VERSION 5.7 ;
  NOWIREEXTENSIONATPIN ON ;
  DIVIDERCHAR "/" ;
  BUSBITCHARS "[]" ;
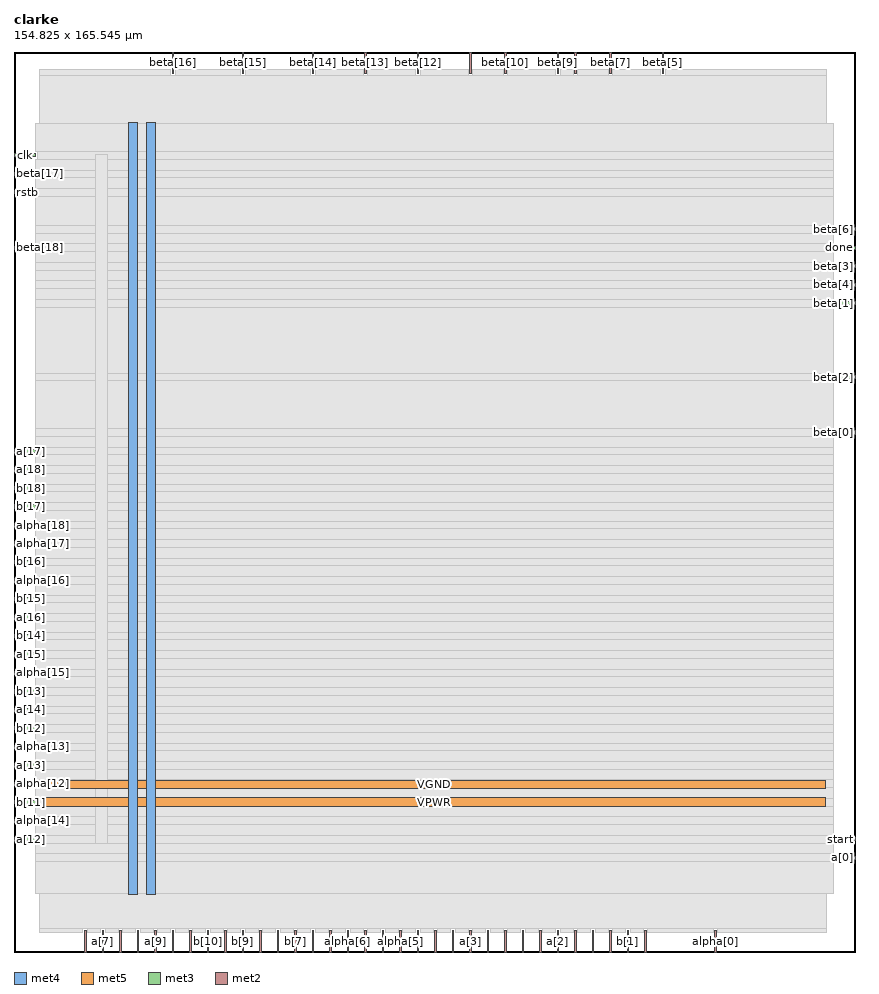
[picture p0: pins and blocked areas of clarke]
MACRO clarke
  CLASS BLOCK ;
  FOREIGN clarke ;
  ORIGIN 0.000 0.000 ;
  SIZE 154.825 BY 165.545 ;
  PIN VGND
    DIRECTION INOUT ;
    USE GROUND ;
    PORT
      LAYER met4 ;
        RECT 24.340 10.640 25.940 152.560 ;
    END
    PORT
      LAYER met5 ;
        RECT 5.280 30.030 149.280 31.630 ;
    END
  END VGND
  PIN VPWR
    DIRECTION INOUT ;
    USE POWER ;
    PORT
      LAYER met4 ;
        RECT 21.040 10.640 22.640 152.560 ;
    END
    PORT
      LAYER met5 ;
        RECT 5.280 26.730 149.280 28.330 ;
    END
  END VPWR
  PIN a[0]
    DIRECTION INPUT ;
    USE SIGNAL ;
    ANTENNAGATEAREA 0.213000 ;
    PORT
      LAYER met3 ;
        RECT 150.825 17.040 154.825 17.640 ;
    END
  END a[0]
  PIN a[10]
    DIRECTION INPUT ;
    USE SIGNAL ;
    ANTENNAGATEAREA 0.196500 ;
    PORT
      LAYER met2 ;
        RECT 12.970 0.000 13.250 4.000 ;
    END
  END a[10]
  PIN a[11]
    DIRECTION INPUT ;
    USE SIGNAL ;
    ANTENNAGATEAREA 0.213000 ;
    PORT
      LAYER met2 ;
        RECT 29.070 0.000 29.350 4.000 ;
    END
  END a[11]
  PIN a[12]
    DIRECTION INPUT ;
    USE SIGNAL ;
    ANTENNAGATEAREA 0.196500 ;
    PORT
      LAYER met3 ;
        RECT 0.000 20.440 4.000 21.040 ;
    END
  END a[12]
  PIN a[13]
    DIRECTION INPUT ;
    USE SIGNAL ;
    ANTENNAGATEAREA 0.196500 ;
    PORT
      LAYER met3 ;
        RECT 0.000 34.040 4.000 34.640 ;
    END
  END a[13]
  PIN a[14]
    DIRECTION INPUT ;
    USE SIGNAL ;
    ANTENNAGATEAREA 0.213000 ;
    PORT
      LAYER met3 ;
        RECT 0.000 44.240 4.000 44.840 ;
    END
  END a[14]
  PIN a[15]
    DIRECTION INPUT ;
    USE SIGNAL ;
    ANTENNAGATEAREA 0.196500 ;
    PORT
      LAYER met3 ;
        RECT 0.000 54.440 4.000 55.040 ;
    END
  END a[15]
  PIN a[16]
    DIRECTION INPUT ;
    USE SIGNAL ;
    ANTENNAGATEAREA 0.196500 ;
    PORT
      LAYER met3 ;
        RECT 0.000 61.240 4.000 61.840 ;
    END
  END a[16]
  PIN a[17]
    DIRECTION INPUT ;
    USE SIGNAL ;
    ANTENNAGATEAREA 0.196500 ;
    PORT
      LAYER met3 ;
        RECT 0.000 91.840 4.000 92.440 ;
    END
  END a[17]
  PIN a[18]
    DIRECTION INPUT ;
    USE SIGNAL ;
    ANTENNAGATEAREA 0.213000 ;
    PORT
      LAYER met3 ;
        RECT 0.000 88.440 4.000 89.040 ;
    END
  END a[18]
  PIN a[1]
    DIRECTION INPUT ;
    USE SIGNAL ;
    ANTENNAGATEAREA 0.196500 ;
    PORT
      LAYER met2 ;
        RECT 116.010 0.000 116.290 4.000 ;
    END
  END a[1]
  PIN a[2]
    DIRECTION INPUT ;
    USE SIGNAL ;
    ANTENNAGATEAREA 0.213000 ;
    PORT
      LAYER met2 ;
        RECT 99.910 0.000 100.190 4.000 ;
    END
  END a[2]
  PIN a[3]
    DIRECTION INPUT ;
    USE SIGNAL ;
    ANTENNAGATEAREA 0.196500 ;
    PORT
      LAYER met2 ;
        RECT 83.810 0.000 84.090 4.000 ;
    END
  END a[3]
  PIN a[4]
    DIRECTION INPUT ;
    USE SIGNAL ;
    ANTENNAGATEAREA 0.196500 ;
    PORT
      LAYER met2 ;
        RECT 109.570 0.000 109.850 4.000 ;
    END
  END a[4]
  PIN a[5]
    DIRECTION INPUT ;
    USE SIGNAL ;
    ANTENNAGATEAREA 0.196500 ;
    PORT
      LAYER met2 ;
        RECT 77.370 0.000 77.650 4.000 ;
    END
  END a[5]
  PIN a[6]
    DIRECTION INPUT ;
    USE SIGNAL ;
    ANTENNAGATEAREA 0.196500 ;
    PORT
      LAYER met2 ;
        RECT 67.710 0.000 67.990 4.000 ;
    END
  END a[6]
  PIN a[7]
    DIRECTION INPUT ;
    USE SIGNAL ;
    ANTENNAGATEAREA 0.495000 ;
    PORT
      LAYER met2 ;
        RECT 16.190 0.000 16.470 4.000 ;
    END
  END a[7]
  PIN a[8]
    DIRECTION INPUT ;
    USE SIGNAL ;
    ANTENNAGATEAREA 0.196500 ;
    PORT
      LAYER met2 ;
        RECT 19.410 0.000 19.690 4.000 ;
    END
  END a[8]
  PIN a[9]
    DIRECTION INPUT ;
    USE SIGNAL ;
    ANTENNAGATEAREA 0.196500 ;
    PORT
      LAYER met2 ;
        RECT 25.850 0.000 26.130 4.000 ;
    END
  END a[9]
  PIN alpha[0]
    DIRECTION OUTPUT ;
    USE SIGNAL ;
    ANTENNADIFFAREA 0.795200 ;
    PORT
      LAYER met2 ;
        RECT 128.890 0.000 129.170 4.000 ;
    END
  END alpha[0]
  PIN alpha[10]
    DIRECTION OUTPUT ;
    USE SIGNAL ;
    ANTENNADIFFAREA 0.795200 ;
    PORT
      LAYER met2 ;
        RECT 38.730 0.000 39.010 4.000 ;
    END
  END alpha[10]
  PIN alpha[11]
    DIRECTION OUTPUT ;
    USE SIGNAL ;
    ANTENNADIFFAREA 0.795200 ;
    PORT
      LAYER met2 ;
        RECT 32.290 0.000 32.570 4.000 ;
    END
  END alpha[11]
  PIN alpha[12]
    DIRECTION OUTPUT ;
    USE SIGNAL ;
    ANTENNADIFFAREA 0.795200 ;
    PORT
      LAYER met3 ;
        RECT 0.000 30.640 4.000 31.240 ;
    END
  END alpha[12]
  PIN alpha[13]
    DIRECTION OUTPUT ;
    USE SIGNAL ;
    ANTENNADIFFAREA 0.795200 ;
    PORT
      LAYER met3 ;
        RECT 0.000 37.440 4.000 38.040 ;
    END
  END alpha[13]
  PIN alpha[14]
    DIRECTION OUTPUT ;
    USE SIGNAL ;
    ANTENNADIFFAREA 0.795200 ;
    PORT
      LAYER met3 ;
        RECT 0.000 23.840 4.000 24.440 ;
    END
  END alpha[14]
  PIN alpha[15]
    DIRECTION OUTPUT ;
    USE SIGNAL ;
    ANTENNADIFFAREA 0.795200 ;
    PORT
      LAYER met3 ;
        RECT 0.000 51.040 4.000 51.640 ;
    END
  END alpha[15]
  PIN alpha[16]
    DIRECTION OUTPUT ;
    USE SIGNAL ;
    ANTENNADIFFAREA 0.795200 ;
    PORT
      LAYER met3 ;
        RECT 0.000 68.040 4.000 68.640 ;
    END
  END alpha[16]
  PIN alpha[17]
    DIRECTION OUTPUT ;
    USE SIGNAL ;
    ANTENNADIFFAREA 0.795200 ;
    PORT
      LAYER met3 ;
        RECT 0.000 74.840 4.000 75.440 ;
    END
  END alpha[17]
  PIN alpha[18]
    DIRECTION OUTPUT ;
    USE SIGNAL ;
    ANTENNADIFFAREA 0.795200 ;
    PORT
      LAYER met3 ;
        RECT 0.000 78.240 4.000 78.840 ;
    END
  END alpha[18]
  PIN alpha[1]
    DIRECTION OUTPUT ;
    USE SIGNAL ;
    ANTENNADIFFAREA 0.795200 ;
    PORT
      LAYER met2 ;
        RECT 106.350 0.000 106.630 4.000 ;
    END
  END alpha[1]
  PIN alpha[2]
    DIRECTION OUTPUT ;
    USE SIGNAL ;
    ANTENNADIFFAREA 0.795200 ;
    PORT
      LAYER met2 ;
        RECT 93.470 0.000 93.750 4.000 ;
    END
  END alpha[2]
  PIN alpha[3]
    DIRECTION OUTPUT ;
    USE SIGNAL ;
    ANTENNADIFFAREA 0.795200 ;
    PORT
      LAYER met2 ;
        RECT 90.250 0.000 90.530 4.000 ;
    END
  END alpha[3]
  PIN alpha[4]
    DIRECTION OUTPUT ;
    USE SIGNAL ;
    ANTENNADIFFAREA 0.795200 ;
    PORT
      LAYER met2 ;
        RECT 80.590 0.000 80.870 4.000 ;
    END
  END alpha[4]
  PIN alpha[5]
    DIRECTION OUTPUT ;
    USE SIGNAL ;
    ANTENNADIFFAREA 0.795200 ;
    PORT
      LAYER met2 ;
        RECT 70.930 0.000 71.210 4.000 ;
    END
  END alpha[5]
  PIN alpha[6]
    DIRECTION OUTPUT ;
    USE SIGNAL ;
    ANTENNADIFFAREA 0.795200 ;
    PORT
      LAYER met2 ;
        RECT 61.270 0.000 61.550 4.000 ;
    END
  END alpha[6]
  PIN alpha[7]
    DIRECTION OUTPUT ;
    USE SIGNAL ;
    ANTENNADIFFAREA 0.795200 ;
    PORT
      LAYER met2 ;
        RECT 54.830 0.000 55.110 4.000 ;
    END
  END alpha[7]
  PIN alpha[8]
    DIRECTION OUTPUT ;
    USE SIGNAL ;
    ANTENNADIFFAREA 0.795200 ;
    PORT
      LAYER met2 ;
        RECT 22.630 0.000 22.910 4.000 ;
    END
  END alpha[8]
  PIN alpha[9]
    DIRECTION OUTPUT ;
    USE SIGNAL ;
    ANTENNADIFFAREA 0.795200 ;
    PORT
      LAYER met2 ;
        RECT 45.170 0.000 45.450 4.000 ;
    END
  END alpha[9]
  PIN b[0]
    DIRECTION INPUT ;
    USE SIGNAL ;
    ANTENNAGATEAREA 0.196500 ;
    PORT
      LAYER met2 ;
        RECT 103.130 0.000 103.410 4.000 ;
    END
  END b[0]
  PIN b[10]
    DIRECTION INPUT ;
    USE SIGNAL ;
    ANTENNAGATEAREA 0.213000 ;
    PORT
      LAYER met2 ;
        RECT 35.510 0.000 35.790 4.000 ;
    END
  END b[10]
  PIN b[11]
    DIRECTION INPUT ;
    USE SIGNAL ;
    ANTENNAGATEAREA 0.196500 ;
    PORT
      LAYER met3 ;
        RECT 0.000 27.240 4.000 27.840 ;
    END
  END b[11]
  PIN b[12]
    DIRECTION INPUT ;
    USE SIGNAL ;
    ANTENNAGATEAREA 0.196500 ;
    PORT
      LAYER met3 ;
        RECT 0.000 40.840 4.000 41.440 ;
    END
  END b[12]
  PIN b[13]
    DIRECTION INPUT ;
    USE SIGNAL ;
    ANTENNAGATEAREA 0.196500 ;
    PORT
      LAYER met3 ;
        RECT 0.000 47.640 4.000 48.240 ;
    END
  END b[13]
  PIN b[14]
    DIRECTION INPUT ;
    USE SIGNAL ;
    ANTENNAGATEAREA 0.196500 ;
    PORT
      LAYER met3 ;
        RECT 0.000 57.840 4.000 58.440 ;
    END
  END b[14]
  PIN b[15]
    DIRECTION INPUT ;
    USE SIGNAL ;
    ANTENNAGATEAREA 0.196500 ;
    PORT
      LAYER met3 ;
        RECT 0.000 64.640 4.000 65.240 ;
    END
  END b[15]
  PIN b[16]
    DIRECTION INPUT ;
    USE SIGNAL ;
    ANTENNAGATEAREA 0.196500 ;
    PORT
      LAYER met3 ;
        RECT 0.000 71.440 4.000 72.040 ;
    END
  END b[16]
  PIN b[17]
    DIRECTION INPUT ;
    USE SIGNAL ;
    ANTENNAGATEAREA 0.196500 ;
    PORT
      LAYER met3 ;
        RECT 0.000 81.640 4.000 82.240 ;
    END
  END b[17]
  PIN b[18]
    DIRECTION INPUT ;
    USE SIGNAL ;
    ANTENNAGATEAREA 0.196500 ;
    PORT
      LAYER met3 ;
        RECT 0.000 85.040 4.000 85.640 ;
    END
  END b[18]
  PIN b[1]
    DIRECTION INPUT ;
    USE SIGNAL ;
    ANTENNAGATEAREA 0.196500 ;
    PORT
      LAYER met2 ;
        RECT 112.790 0.000 113.070 4.000 ;
    END
  END b[1]
  PIN b[2]
    DIRECTION INPUT ;
    USE SIGNAL ;
    ANTENNAGATEAREA 0.196500 ;
    PORT
      LAYER met2 ;
        RECT 87.030 0.000 87.310 4.000 ;
    END
  END b[2]
  PIN b[3]
    DIRECTION INPUT ;
    USE SIGNAL ;
    ANTENNAGATEAREA 0.196500 ;
    PORT
      LAYER met2 ;
        RECT 96.690 0.000 96.970 4.000 ;
    END
  END b[3]
  PIN b[4]
    DIRECTION INPUT ;
    USE SIGNAL ;
    ANTENNAGATEAREA 0.196500 ;
    PORT
      LAYER met2 ;
        RECT 74.150 0.000 74.430 4.000 ;
    END
  END b[4]
  PIN b[5]
    DIRECTION INPUT ;
    USE SIGNAL ;
    ANTENNAGATEAREA 0.196500 ;
    PORT
      LAYER met2 ;
        RECT 64.490 0.000 64.770 4.000 ;
    END
  END b[5]
  PIN b[6]
    DIRECTION INPUT ;
    USE SIGNAL ;
    ANTENNAGATEAREA 0.196500 ;
    PORT
      LAYER met2 ;
        RECT 58.050 0.000 58.330 4.000 ;
    END
  END b[6]
  PIN b[7]
    DIRECTION INPUT ;
    USE SIGNAL ;
    ANTENNAGATEAREA 0.196500 ;
    PORT
      LAYER met2 ;
        RECT 51.610 0.000 51.890 4.000 ;
    END
  END b[7]
  PIN b[8]
    DIRECTION INPUT ;
    USE SIGNAL ;
    ANTENNAGATEAREA 0.196500 ;
    PORT
      LAYER met2 ;
        RECT 48.390 0.000 48.670 4.000 ;
    END
  END b[8]
  PIN b[9]
    DIRECTION INPUT ;
    USE SIGNAL ;
    ANTENNAGATEAREA 0.196500 ;
    PORT
      LAYER met2 ;
        RECT 41.950 0.000 42.230 4.000 ;
    END
  END b[9]
  PIN beta[0]
    DIRECTION OUTPUT ;
    USE SIGNAL ;
    ANTENNADIFFAREA 0.795200 ;
    PORT
      LAYER met3 ;
        RECT 150.825 95.240 154.825 95.840 ;
    END
  END beta[0]
  PIN beta[10]
    DIRECTION OUTPUT ;
    USE SIGNAL ;
    ANTENNADIFFAREA 0.795200 ;
    PORT
      LAYER met2 ;
        RECT 90.250 161.545 90.530 165.545 ;
    END
  END beta[10]
  PIN beta[11]
    DIRECTION OUTPUT ;
    USE SIGNAL ;
    ANTENNADIFFAREA 0.795200 ;
    PORT
      LAYER met2 ;
        RECT 83.810 161.545 84.090 165.545 ;
    END
  END beta[11]
  PIN beta[12]
    DIRECTION OUTPUT ;
    USE SIGNAL ;
    ANTENNADIFFAREA 0.795200 ;
    PORT
      LAYER met2 ;
        RECT 74.150 161.545 74.430 165.545 ;
    END
  END beta[12]
  PIN beta[13]
    DIRECTION OUTPUT ;
    USE SIGNAL ;
    ANTENNADIFFAREA 0.795200 ;
    PORT
      LAYER met2 ;
        RECT 64.490 161.545 64.770 165.545 ;
    END
  END beta[13]
  PIN beta[14]
    DIRECTION OUTPUT ;
    USE SIGNAL ;
    ANTENNADIFFAREA 0.795200 ;
    PORT
      LAYER met2 ;
        RECT 54.830 161.545 55.110 165.545 ;
    END
  END beta[14]
  PIN beta[15]
    DIRECTION OUTPUT ;
    USE SIGNAL ;
    ANTENNADIFFAREA 0.795200 ;
    PORT
      LAYER met2 ;
        RECT 41.950 161.545 42.230 165.545 ;
    END
  END beta[15]
  PIN beta[16]
    DIRECTION OUTPUT ;
    USE SIGNAL ;
    ANTENNADIFFAREA 0.795200 ;
    PORT
      LAYER met2 ;
        RECT 29.070 161.545 29.350 165.545 ;
    END
  END beta[16]
  PIN beta[17]
    DIRECTION OUTPUT ;
    USE SIGNAL ;
    ANTENNADIFFAREA 0.795200 ;
    PORT
      LAYER met3 ;
        RECT 0.000 142.840 4.000 143.440 ;
    END
  END beta[17]
  PIN beta[18]
    DIRECTION OUTPUT ;
    USE SIGNAL ;
    ANTENNADIFFAREA 0.795200 ;
    PORT
      LAYER met3 ;
        RECT 0.000 129.240 4.000 129.840 ;
    END
  END beta[18]
  PIN beta[1]
    DIRECTION OUTPUT ;
    USE SIGNAL ;
    ANTENNADIFFAREA 0.445500 ;
    PORT
      LAYER met3 ;
        RECT 150.825 119.040 154.825 119.640 ;
    END
  END beta[1]
  PIN beta[2]
    DIRECTION OUTPUT ;
    USE SIGNAL ;
    ANTENNADIFFAREA 0.445500 ;
    PORT
      LAYER met3 ;
        RECT 150.825 105.440 154.825 106.040 ;
    END
  END beta[2]
  PIN beta[3]
    DIRECTION OUTPUT ;
    USE SIGNAL ;
    ANTENNADIFFAREA 0.795200 ;
    PORT
      LAYER met3 ;
        RECT 150.825 125.840 154.825 126.440 ;
    END
  END beta[3]
  PIN beta[4]
    DIRECTION OUTPUT ;
    USE SIGNAL ;
    ANTENNADIFFAREA 0.795200 ;
    PORT
      LAYER met3 ;
        RECT 150.825 122.440 154.825 123.040 ;
    END
  END beta[4]
  PIN beta[5]
    DIRECTION OUTPUT ;
    USE SIGNAL ;
    ANTENNADIFFAREA 0.795200 ;
    PORT
      LAYER met2 ;
        RECT 119.230 161.545 119.510 165.545 ;
    END
  END beta[5]
  PIN beta[6]
    DIRECTION OUTPUT ;
    USE SIGNAL ;
    ANTENNADIFFAREA 0.445500 ;
    PORT
      LAYER met3 ;
        RECT 150.825 132.640 154.825 133.240 ;
    END
  END beta[6]
  PIN beta[7]
    DIRECTION OUTPUT ;
    USE SIGNAL ;
    ANTENNADIFFAREA 0.795200 ;
    PORT
      LAYER met2 ;
        RECT 109.570 161.545 109.850 165.545 ;
    END
  END beta[7]
  PIN beta[8]
    DIRECTION OUTPUT ;
    USE SIGNAL ;
    ANTENNADIFFAREA 0.795200 ;
    PORT
      LAYER met2 ;
        RECT 103.130 161.545 103.410 165.545 ;
    END
  END beta[8]
  PIN beta[9]
    DIRECTION OUTPUT ;
    USE SIGNAL ;
    ANTENNADIFFAREA 0.795200 ;
    PORT
      LAYER met2 ;
        RECT 99.910 161.545 100.190 165.545 ;
    END
  END beta[9]
  PIN clk
    DIRECTION INPUT ;
    USE SIGNAL ;
    ANTENNAGATEAREA 0.852000 ;
    PORT
      LAYER met3 ;
        RECT 0.000 146.240 4.000 146.840 ;
    END
  END clk
  PIN done
    DIRECTION OUTPUT ;
    USE SIGNAL ;
    ANTENNADIFFAREA 0.795200 ;
    PORT
      LAYER met3 ;
        RECT 150.825 129.240 154.825 129.840 ;
    END
  END done
  PIN rstb
    DIRECTION INPUT ;
    USE SIGNAL ;
    ANTENNAGATEAREA 0.213000 ;
    PORT
      LAYER met3 ;
        RECT 0.000 139.440 4.000 140.040 ;
    END
  END rstb
  PIN start
    DIRECTION INPUT ;
    USE SIGNAL ;
    ANTENNAGATEAREA 0.159000 ;
    PORT
      LAYER met3 ;
        RECT 150.825 20.440 154.825 21.040 ;
    END
  END start
  OBS
      LAYER li1 ;
        RECT 5.520 10.795 149.040 152.405 ;
      LAYER met1 ;
        RECT 4.670 6.840 149.430 152.560 ;
      LAYER met2 ;
        RECT 4.690 161.265 28.790 162.250 ;
        RECT 29.630 161.265 41.670 162.250 ;
        RECT 42.510 161.265 54.550 162.250 ;
        RECT 55.390 161.265 64.210 162.250 ;
        RECT 65.050 161.265 73.870 162.250 ;
        RECT 74.710 161.265 83.530 162.250 ;
        RECT 84.370 161.265 89.970 162.250 ;
        RECT 90.810 161.265 99.630 162.250 ;
        RECT 100.470 161.265 102.850 162.250 ;
        RECT 103.690 161.265 109.290 162.250 ;
        RECT 110.130 161.265 118.950 162.250 ;
        RECT 119.790 161.265 149.410 162.250 ;
        RECT 4.690 4.280 149.410 161.265 ;
        RECT 4.690 3.670 12.690 4.280 ;
        RECT 13.530 3.670 15.910 4.280 ;
        RECT 16.750 3.670 19.130 4.280 ;
        RECT 19.970 3.670 22.350 4.280 ;
        RECT 23.190 3.670 25.570 4.280 ;
        RECT 26.410 3.670 28.790 4.280 ;
        RECT 29.630 3.670 32.010 4.280 ;
        RECT 32.850 3.670 35.230 4.280 ;
        RECT 36.070 3.670 38.450 4.280 ;
        RECT 39.290 3.670 41.670 4.280 ;
        RECT 42.510 3.670 44.890 4.280 ;
        RECT 45.730 3.670 48.110 4.280 ;
        RECT 48.950 3.670 51.330 4.280 ;
        RECT 52.170 3.670 54.550 4.280 ;
        RECT 55.390 3.670 57.770 4.280 ;
        RECT 58.610 3.670 60.990 4.280 ;
        RECT 61.830 3.670 64.210 4.280 ;
        RECT 65.050 3.670 67.430 4.280 ;
        RECT 68.270 3.670 70.650 4.280 ;
        RECT 71.490 3.670 73.870 4.280 ;
        RECT 74.710 3.670 77.090 4.280 ;
        RECT 77.930 3.670 80.310 4.280 ;
        RECT 81.150 3.670 83.530 4.280 ;
        RECT 84.370 3.670 86.750 4.280 ;
        RECT 87.590 3.670 89.970 4.280 ;
        RECT 90.810 3.670 93.190 4.280 ;
        RECT 94.030 3.670 96.410 4.280 ;
        RECT 97.250 3.670 99.630 4.280 ;
        RECT 100.470 3.670 102.850 4.280 ;
        RECT 103.690 3.670 106.070 4.280 ;
        RECT 106.910 3.670 109.290 4.280 ;
        RECT 110.130 3.670 112.510 4.280 ;
        RECT 113.350 3.670 115.730 4.280 ;
        RECT 116.570 3.670 128.610 4.280 ;
        RECT 129.450 3.670 149.410 4.280 ;
      LAYER met3 ;
        RECT 3.990 147.240 150.825 152.485 ;
        RECT 4.400 145.840 150.825 147.240 ;
        RECT 3.990 143.840 150.825 145.840 ;
        RECT 4.400 142.440 150.825 143.840 ;
        RECT 3.990 140.440 150.825 142.440 ;
        RECT 4.400 139.040 150.825 140.440 ;
        RECT 3.990 133.640 150.825 139.040 ;
        RECT 3.990 132.240 150.425 133.640 ;
        RECT 3.990 130.240 150.825 132.240 ;
        RECT 4.400 128.840 150.425 130.240 ;
        RECT 3.990 126.840 150.825 128.840 ;
        RECT 3.990 125.440 150.425 126.840 ;
        RECT 3.990 123.440 150.825 125.440 ;
        RECT 3.990 122.040 150.425 123.440 ;
        RECT 3.990 120.040 150.825 122.040 ;
        RECT 3.990 118.640 150.425 120.040 ;
        RECT 3.990 106.440 150.825 118.640 ;
        RECT 3.990 105.040 150.425 106.440 ;
        RECT 3.990 96.240 150.825 105.040 ;
        RECT 3.990 94.840 150.425 96.240 ;
        RECT 3.990 92.840 150.825 94.840 ;
        RECT 4.400 91.440 150.825 92.840 ;
        RECT 3.990 89.440 150.825 91.440 ;
        RECT 4.400 88.040 150.825 89.440 ;
        RECT 3.990 86.040 150.825 88.040 ;
        RECT 4.400 84.640 150.825 86.040 ;
        RECT 3.990 82.640 150.825 84.640 ;
        RECT 4.400 81.240 150.825 82.640 ;
        RECT 3.990 79.240 150.825 81.240 ;
        RECT 4.400 77.840 150.825 79.240 ;
        RECT 3.990 75.840 150.825 77.840 ;
        RECT 4.400 74.440 150.825 75.840 ;
        RECT 3.990 72.440 150.825 74.440 ;
        RECT 4.400 71.040 150.825 72.440 ;
        RECT 3.990 69.040 150.825 71.040 ;
        RECT 4.400 67.640 150.825 69.040 ;
        RECT 3.990 65.640 150.825 67.640 ;
        RECT 4.400 64.240 150.825 65.640 ;
        RECT 3.990 62.240 150.825 64.240 ;
        RECT 4.400 60.840 150.825 62.240 ;
        RECT 3.990 58.840 150.825 60.840 ;
        RECT 4.400 57.440 150.825 58.840 ;
        RECT 3.990 55.440 150.825 57.440 ;
        RECT 4.400 54.040 150.825 55.440 ;
        RECT 3.990 52.040 150.825 54.040 ;
        RECT 4.400 50.640 150.825 52.040 ;
        RECT 3.990 48.640 150.825 50.640 ;
        RECT 4.400 47.240 150.825 48.640 ;
        RECT 3.990 45.240 150.825 47.240 ;
        RECT 4.400 43.840 150.825 45.240 ;
        RECT 3.990 41.840 150.825 43.840 ;
        RECT 4.400 40.440 150.825 41.840 ;
        RECT 3.990 38.440 150.825 40.440 ;
        RECT 4.400 37.040 150.825 38.440 ;
        RECT 3.990 35.040 150.825 37.040 ;
        RECT 4.400 33.640 150.825 35.040 ;
        RECT 3.990 31.640 150.825 33.640 ;
        RECT 4.400 30.240 150.825 31.640 ;
        RECT 3.990 28.240 150.825 30.240 ;
        RECT 4.400 26.840 150.825 28.240 ;
        RECT 3.990 24.840 150.825 26.840 ;
        RECT 4.400 23.440 150.825 24.840 ;
        RECT 3.990 21.440 150.825 23.440 ;
        RECT 4.400 20.040 150.425 21.440 ;
        RECT 3.990 18.040 150.825 20.040 ;
        RECT 3.990 16.640 150.425 18.040 ;
        RECT 3.990 10.715 150.825 16.640 ;
      LAYER met4 ;
        RECT 15.015 19.895 17.185 146.705 ;
  END
END clarke
END LIBRARY

